VERSION 5.7 ;
  NOWIREEXTENSIONATPIN ON ;
  DIVIDERCHAR "/" ;
  BUSBITCHARS "[]" ;
UNITS
  DATABASE MICRONS 1000 ;
END UNITS

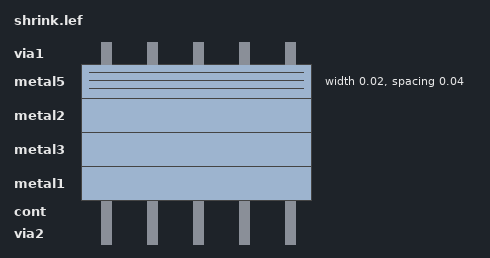
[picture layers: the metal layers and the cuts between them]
LAYER via2
  TYPE CUT ;
END via2

LAYER NWELL
  TYPE MASTERSLICE ;
END NWELL

LAYER cont
  TYPE CUT ;
END cont

LAYER metal1
  TYPE ROUTING ;
END metal1

LAYER metal3
  TYPE ROUTING ;
END metal3

LAYER metal2
  TYPE ROUTING ;
END metal2

LAYER metal5
  TYPE ROUTING ;
  WIDTH 0.020000 ;
  SPACING 0.040000 ;
  DIRECTION HORIZONTAL ;
END metal5

LAYER POLY
  TYPE MASTERSLICE ;
END POLY

LAYER via1
  TYPE CUT ;
END via1

MACRO top2
  CLASS BLOCK ;
  FOREIGN top2 ;
  ORIGIN 0.000 0.000 ;
  SIZE 0.200 BY 0.200 ;
  OBS
      LAYER metal1 ;
        RECT 0.000 0.000 0.200 0.200 ;
  END
END top2
END LIBRARY

